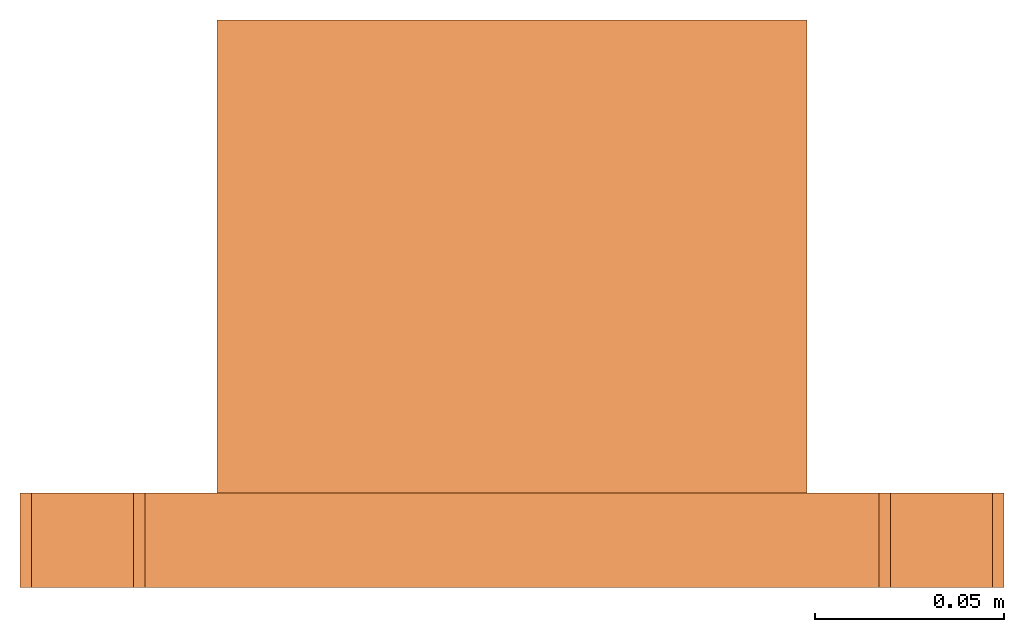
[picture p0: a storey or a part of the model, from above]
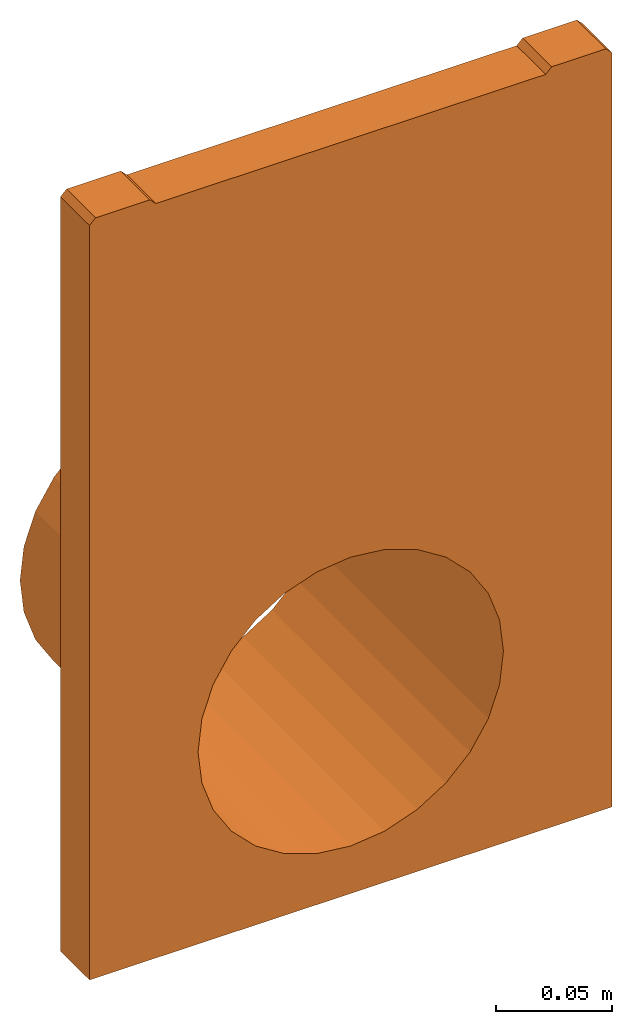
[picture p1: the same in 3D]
Properties of the parts of a building model (IFC2X3)

# File
Description: ViewDefinition [CoordinationView]
File name: 33108 - PD200 F 108 Inlet outlet endcap.ifc
Time: 2013-10-11T12:56:40
Written by: Autodesk Revit 2013
Made in: 20120221_2030(x64)

# IfcProject, Project Number
LongName: Project Name; Phase: Project Status

# IfcSite, Default
RefLatitude: 42, 21, 30, 344238; RefLongitude: -71, -3, -35, -194702; RefElevation: 0 mm

# IfcBuilding
Pset_BuildingCommon - NumberOfStoreys: 2
Other - Project Address: Enter address here; Project Name: Project Name; Project Status: Project Status; Client Name: Owner; Project Issue Date: Issue Date; Project Number: Project Number

# IfcBuildingStorey (2)
Graphics - Symbol: M_Level Head - Circle: M_Level Head - Circle; Symbol at End 1 Default: no; Symbol at End 2 Default: yes; Color: 0; Line Pattern: Center; Line Weight: 1
Constraints - Elevation Base: 0
Identity Data - Structural: no; Building Story: yes
Dimensions - Computation Height: 0 mm
Name | LongName = Name | Elevation (mm) = Constraints, Elevation (mm)
B.O. Footing | B.O. Footing | -4600
T.O. Footing | T.O. Footing | -4300

# IfcBuildingElementProxy: 33108 - PD200 F 108 Inlet/outlet endcap, Civil-Drainage-Channel-ACO-RoadDrain 200:33108 - PD200 F 108 Inlet/outlet endcap:33108 - PD200 F 108 Inlet/outlet endcap:309971
In: B.O. Footing
Material: Phenolic Resin, Acetal Resin, Black
Construction - Closing End Cap: no; Access unit: no; Inlet Outlet end cap: yes; Channel 260mm Wide: no
Other - CreatedBy: www.aco.co.uk; Revision: 1
Green Building Properties - End Cap Recycled Material Content: 20% minimum; Channel Recyclable: N/A; Access Cover/Frame Recycled Material Content: N/A; Access Cover/Frame Recyclable: N/A; End Cap Recyclable: Fully recyclable; Channel Recycled Material Content: N/A
Data - Product Standard: N/A; Product Weight: 4.3 Kg; Invert Depth: N/A; Hydraulic Performance: N/A; Channel C.S.A: N/A; Load Class: N/A; Product Dimensions: 25mm x 260mm x 400mm (LxWxH); Concrete Surround Volume - Load Class F 900 - Concrete Pavement: N/A; Connection Pipe O.D: Ø160mm; ACO Hydraulic Design Software: N/A; Installation - Concrete Grade: N/A
Dimensions - Length: 500 mm; Volume: 2252322 mm3; Custom Void Length: 0 mm; Straight Void Length: 25 mm; Invert Depth.: 270 mm; I/O End Cap Void: 128.041 mm; Total Depth: 400 mm; Void Depth: -400 mm; Pipe Depth: 299 mm; Straight Void Start: 0 mm
Constraints - Moves With Nearby Elements: no; Level: Level: T.O. Footing
Phasing - Phase Created: Phase 1
Pset_BuildingElementProxyCommon - Reference: 33108 - PD200 F 108 Inlet/outlet endcap
Identity Data - Product brochure: http://www.aco.co.uk/download.php?id=256; Watermarked By: www.aco.co.uk; Model: ACO RoadDrain 200 PD200F; Cost: 0; Watermarked With: BIM Manager Premium Suite; Manufacturer: ACO Technologies plc - ACO Water Management Division; Watermark 2: This file is water marked and users are prohibited to reproduce, adapt, distribute this information; Maintenance guidelines: http://www.aco.co.uk/download.php?id=256; URL: www.aco.co.uk; Address: ACO Business Park, Hitchin Road, Shefford, Bedfordshire, United Kingdom SG17 5TE; Watermark 1: This file is the property of ACO Technologies PLC; Price: POA - contact ACO; Assembly Code: D2040; OmniClass Title: Rainwater Removal; Product Code: 33108; OmniClass Number: 23.70.50.24; Product Page URL: http://www.aco.co.uk/product_detail.php?id=21; Assembly Description: Rain Water Drainage; e-mail Sales: customersupport@aco.co.uk; Installation guidelines: http://www.aco.co.uk/download.php?id=256; Telephone: +44 (0)1462 816666; Model Description: Monolithic Channel drainage system; Type Comments: ACO RoadDrain PD200 F 108 Inlet/Outlet End Cap; e-mail Technical: technical@aco.co.uk; Fax: +44 (0)1462 815895
General - TagNumber: 0.000000; SerialNumber: 0.000000
Materials and Finishes - Connection Pipe Material: PVCu; Connection Pipe Colour: Brown; Channel Colour: N/A; End Cap Colour: Black; Access Cover/Frame Finish: N/A; Channel Material: N/A; Grating Colour: N/A; Access Cover/Frame Colour: N/A; Access Cover/Frame Material: N/A; Grating Material: N/A; End Cap Material: Vienite® Synthetic Resin Concrete; Grating Finish: N/A

# IfcOpeningElement: Recess
In: T.O. Footing
Dimensions - Area: 26010000 mm2; Volume: 40310511426 mm3; Thickness: 1550 mm; Perimeter: 20400 mm
Constraints - Related to Mass: no; Height Offset From Level: 0 mm; Room Bounding: yes; Level: Level: T.O. Footing
Structural - Structural: no; Enable Analytical Model: no
Phasing - Phase Created: Phase 1
Graphics - Coarse Scale Fill Color: 0
Construction - Default Thickness: 1550 mm; Function: 0
Materials and Finishes - Structural Material: Grass
Analytical Properties - Absorptance: 0.1; Roughness: 1; Heat Transfer Coefficient (U): 0.558; Thermal mass: 2039700; Thermal Resistance (R): 1.79211

# IfcSlab: Floor:Generic Floor - 400mm, Floor:Generic Floor - 400mm:136436
In: T.O. Footing
PredefinedType: FLOOR; Material: Grass 50 mm, Earth 1500 mm
Dimensions - Area: 26010000 mm2; Volume: 40310511426 mm3; Thickness: 1550 mm; Perimeter: 20400 mm
Constraints - Related to Mass: no; Height Offset From Level: 0 mm; Room Bounding: yes; Level: Level: T.O. Footing
Structural - Structural: no; Enable Analytical Model: no
Phasing - Phase Created: Phase 1
Pset_SlabCommon - Reference: Generic Floor - 400mm; IsExternal: no; LoadBearing: yes
Graphics - Coarse Scale Fill Color: 0
Construction - Default Thickness: 1550 mm; Function: 0
Materials and Finishes - Structural Material: Grass
Analytical Properties - Absorptance: 0.1; Roughness: 1; Heat Transfer Coefficient (U): 0.558; Thermal mass: 2039700; Thermal Resistance (R): 1.79211
